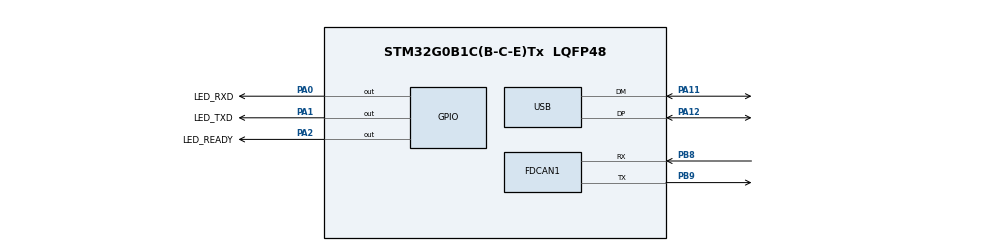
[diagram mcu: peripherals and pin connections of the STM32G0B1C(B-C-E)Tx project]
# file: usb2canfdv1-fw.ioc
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FDCAN1.AutoRetransmission=ENABLE
FDCAN1.CalculateBaudRateNominal=166666
FDCAN1.CalculateTimeBitNominal=6000
FDCAN1.CalculateTimeQuantumNominal=50.0
FDCAN1.DataPrescaler=2
FDCAN1.DataSyncJumpWidth=3
FDCAN1.DataTimeSeg1=10
FDCAN1.DataTimeSeg2=4
FDCAN1.ExtFiltersNbr=2
FDCAN1.NominalPrescaler=4
FDCAN1.NominalSyncJumpWidth=13
FDCAN1.NominalTimeSeg1=105
FDCAN1.NominalTimeSeg2=14
FDCAN1.ProtocolException=ENABLE
FDCAN1.StdFiltersNbr=2
Mcu.Family=STM32G0
Mcu.Name=STM32G0B1C(B-C-E)Tx
Mcu.Package=LQFP48
NVIC.USB_UCPD1_2_IRQn=true\:0\:0\:false\:false\:true\:true\:true\:true
PA0.GPIO_Label=LED_RXD
PA0.Signal=GPIO_Output
PA1.GPIO_Label=LED_TXD
PA1.Signal=GPIO_Output
PA11\ [PA9].Mode=Device
PA11\ [PA9].Signal=USB_DM
PA12\ [PA10].Mode=Device
PA12\ [PA10].Signal=USB_DP
PA13.Mode=Serial_Wire
PA13.Signal=SYS_SWDIO
PA14-BOOT0.Mode=Serial_Wire
PA14-BOOT0.Signal=SYS_SWCLK
PA2.GPIO_Label=LED_READY
PA2.Signal=GPIO_Output
PB8.Mode=FDCAN_Activate
PB8.Signal=FDCAN1_RX
PB9.Mode=FDCAN_Activate
PB9.Signal=FDCAN1_TX
PF0-OSC_IN\ (PF0).Mode=HSE-External-Oscillator
PF0-OSC_IN\ (PF0).Signal=RCC_OSC_IN
PF1-OSC_OUT\ (PF1).Mode=HSE-External-Oscillator
PF1-OSC_OUT\ (PF1).Signal=RCC_OSC_OUT
ProjectManager.HeapSize=0x400
ProjectManager.StackSize=0x400
ProjectManager.TargetToolchain=STM32CubeIDE
RCC.ADCFreq_Value=64000000
RCC.AHBFreq_Value=64000000
RCC.CortexFreq_Value=64000000
RCC.EXTERNAL_CLOCK_VALUE=48000
RCC.FDCANCLockSelection=RCC_FDCANCLKSOURCE_PLL
RCC.HCLKFreq_Value=64000000
RCC.HSE_VALUE=16000000
RCC.HSI48_VALUE=48000000
RCC.HSI_VALUE=16000000
RCC.LSE_VALUE=32768
RCC.PLLN=20
RCC.PLLQ=RCC_PLLQ_DIV4
RCC.PLLR=RCC_PLLR_DIV5
RCC.PLLSourceVirtual=RCC_PLLSOURCE_HSE
RCC.SYSCLKFreq_VALUE=64000000
RCC.SYSCLKSource=RCC_SYSCLKSOURCE_PLLCLK
RCC.USBFreq_Value=48000000
RCC.VCOOutputFreq_Value=320000000
TIM3.Prescaler=63
USB_DEVICE.APP_RX_DATA_SIZE=64
USB_DEVICE.APP_TX_DATA_SIZE=64
USB_DEVICE.CLASS_NAME_FS=CDC
USB_DEVICE.PRODUCT_STRING_CDC_FS=CANFD to Virtual Com Adapter
USB_DEVICE.VirtualMode=Cdc
USB_DEVICE.VirtualModeFS=Cdc_FS
VP_SYS_VS_DBSignals.Mode=DisableDeadBatterySignals
VP_TIM3_VS_ClockSourceINT.Mode=Internal
VP_USB_DEVICE_VS_USB_DEVICE_CDC_FS.Mode=CDC_FS
board=custom

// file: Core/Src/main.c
/* USER CODE BEGIN Header */
/**
  ******************************************************************************
  * @file           : main.c
  * @brief          : Main program body
  ******************************************************************************
  * @attention
  *
  * Copyright (c) 2024 STMicroelectronics.
  * All rights reserved.
  *
  * This software is licensed under terms that can be found in the LICENSE file
  * in the root directory of this software component.
  * If no LICENSE file comes with this software, it is provided AS-IS.
  *
  ******************************************************************************
  */
/* USER CODE END Header */
#include "main.h"
#include "fdcan.h"
#include "tim.h"
#include "usb_device.h"
#include "gpio.h"

/* USER CODE BEGIN Includes */
#include "bootloader.h"
#include "usbd_cdc_if.h"
#include "buffer.h"
#include "can.h"
#include "led.h"
#include "nvm.h"
#include "slcan.h"
/* USER CODE END Includes */

void SystemClock_Config(void);

int main(void)
{

  /* USER CODE BEGIN 1 */
  bootloader_init();
  /* USER CODE END 1 */

  /* MCU Configuration--------------------------------------------------------*/

  /* Reset of all peripherals, Initializes the Flash interface and the Systick. */
  HAL_Init();

  /* Configure the system clock */
  SystemClock_Config();

  /* Initialize all configured peripherals */
  MX_GPIO_Init();
  MX_FDCAN1_Init();
  MX_USB_Device_Init();
  MX_TIM3_Init();
  /* USER CODE BEGIN 2 */
  led_init();
  buf_init();
  can_init();
  nvm_init();
  led_blink_sequence(5);
  nvm_apply_startup_cfg();
  /* USER CODE END 2 */

  /* Infinite loop */
  while (1)
  {

    /* USER CODE BEGIN 3 */
    led_process();
    can_process();
    buf_process();
  }
  /* USER CODE END 3 */
}

void SystemClock_Config(void)
{
  RCC_OscInitTypeDef RCC_OscInitStruct = {0};
  RCC_ClkInitTypeDef RCC_ClkInitStruct = {0};

  /** Configure the main internal regulator output voltage
  */
  HAL_PWREx_ControlVoltageScaling(PWR_REGULATOR_VOLTAGE_SCALE1);

  /** Initializes the RCC Oscillators according to the specified parameters
  * in the RCC_OscInitTypeDef structure.
  */
  RCC_OscInitStruct.OscillatorType = RCC_OSCILLATORTYPE_HSE|RCC_OSCILLATORTYPE_HSI48;
  RCC_OscInitStruct.HSEState = RCC_HSE_ON;
  RCC_OscInitStruct.HSI48State = RCC_HSI48_ON;
  RCC_OscInitStruct.PLL.PLLState = RCC_PLL_ON;
  RCC_OscInitStruct.PLL.PLLSource = RCC_PLLSOURCE_HSE;
  RCC_OscInitStruct.PLL.PLLM = RCC_PLLM_DIV1;
  RCC_OscInitStruct.PLL.PLLN = 15;
  RCC_OscInitStruct.PLL.PLLP = RCC_PLLP_DIV2;
  RCC_OscInitStruct.PLL.PLLQ = RCC_PLLQ_DIV8;
  RCC_OscInitStruct.PLL.PLLR = RCC_PLLR_DIV4;
  if (HAL_RCC_OscConfig(&RCC_OscInitStruct) != HAL_OK)
  {
    Error_Handler();
  }

  /** Initializes the CPU, AHB and APB buses clocks
  */
  RCC_ClkInitStruct.ClockType = RCC_CLOCKTYPE_HCLK|RCC_CLOCKTYPE_SYSCLK
                              |RCC_CLOCKTYPE_PCLK1;
  RCC_ClkInitStruct.SYSCLKSource = RCC_SYSCLKSOURCE_PLLCLK;
  RCC_ClkInitStruct.AHBCLKDivider = RCC_SYSCLK_DIV1;
  RCC_ClkInitStruct.APB1CLKDivider = RCC_HCLK_DIV1;

  if (HAL_RCC_ClockConfig(&RCC_ClkInitStruct, FLASH_LATENCY_2) != HAL_OK)
  {
    Error_Handler();
  }
}

void Error_Handler(void)
{
  __disable_irq();
  while (1)
  {
  }
}
